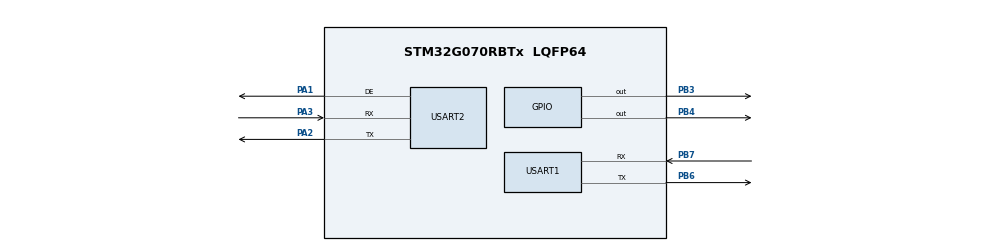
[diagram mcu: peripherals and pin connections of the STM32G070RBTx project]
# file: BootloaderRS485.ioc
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Dma.Request0=USART2_RX
Dma.USART2_RX.0.Direction=DMA_PERIPH_TO_MEMORY
Dma.USART2_RX.0.EventEnable=DISABLE
Dma.USART2_RX.0.Instance=DMA1_Channel1
Dma.USART2_RX.0.MemDataAlignment=DMA_MDATAALIGN_BYTE
Dma.USART2_RX.0.MemInc=DMA_MINC_ENABLE
Dma.USART2_RX.0.Mode=DMA_NORMAL
Dma.USART2_RX.0.PeriphDataAlignment=DMA_PDATAALIGN_BYTE
Dma.USART2_RX.0.PeriphInc=DMA_PINC_DISABLE
Dma.USART2_RX.0.Polarity=HAL_DMAMUX_REQ_GEN_RISING
Dma.USART2_RX.0.Priority=DMA_PRIORITY_LOW
Dma.USART2_RX.0.RequestNumber=1
Dma.USART2_RX.0.SignalID=NONE
Dma.USART2_RX.0.SyncEnable=DISABLE
Dma.USART2_RX.0.SyncPolarity=HAL_DMAMUX_SYNC_NO_EVENT
Dma.USART2_RX.0.SyncRequestNumber=1
Dma.USART2_RX.0.SyncSignalID=NONE
IWDG.Prescaler=IWDG_PRESCALER_4
Mcu.Family=STM32G0
Mcu.Name=STM32G070RBTx
Mcu.Package=LQFP64
NVIC.DMA1_Channel1_IRQn=true\:0\:0\:false\:false\:true\:false\:true\:true
NVIC.USART2_IRQn=true\:0\:0\:false\:false\:true\:true\:true\:true
PA1.Mode=Hardware Flow Control (RS485)
PA1.Signal=USART2_DE
PA2.Mode=Asynchronous
PA2.Signal=USART2_TX
PA3.Mode=Asynchronous
PA3.Signal=USART2_RX
PB3.Signal=GPIO_Output
PB4.Signal=GPIO_Output
PB6.Mode=Asynchronous
PB6.Signal=USART1_TX
PB7.Mode=Asynchronous
PB7.Signal=USART1_RX
PF0-OSC_IN\ (PF0).Mode=HSE-External-Oscillator
PF0-OSC_IN\ (PF0).Signal=RCC_OSC_IN
PF1-OSC_OUT\ (PF1).Mode=HSE-External-Oscillator
PF1-OSC_OUT\ (PF1).Signal=RCC_OSC_OUT
ProjectManager.HeapSize=0x200
ProjectManager.StackSize=0x400
ProjectManager.TargetToolchain=STM32CubeIDE
RCC.ADCFreq_Value=32000000
RCC.AHBFreq_Value=32000000
RCC.CortexFreq_Value=32000000
RCC.EXTERNAL_CLOCK_VALUE=48000
RCC.HCLKFreq_Value=32000000
RCC.HSE_VALUE=8000000
RCC.HSI_VALUE=16000000
RCC.LSE_VALUE=32768
RCC.PLLSourceVirtual=RCC_PLLSOURCE_HSE
RCC.SYSCLKFreq_VALUE=32000000
RCC.SYSCLKSource=RCC_SYSCLKSOURCE_PLLCLK
RCC.VCOOutputFreq_Value=64000000
USART1.VirtualMode-Asynchronous=VM_ASYNC
USART2.VirtualMode-Asynchronous=VM_ASYNC
USART2.VirtualMode-Hardware\ Flow\ Control\ (RS485)=VM_ASYNC
VP_IWDG_VS_IWDG.Mode=IWDG_Activate
board=custom

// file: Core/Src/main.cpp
/* USER CODE BEGIN Header */
/**
  ******************************************************************************
  * @file           : main.c
  * @brief          : Main program body
  ******************************************************************************
  * @attention
  *
  * Copyright (c) 2023 STMicroelectronics.
  * All rights reserved.
  *
  * This software is licensed under terms that can be found in the LICENSE file
  * in the root directory of this software component.
  * If no LICENSE file comes with this software, it is provided AS-IS.
  *
  ******************************************************************************
  */
/* USER CODE END Header */
#include "main.h"

/* USER CODE BEGIN Includes */
#include "RS485.hpp"
#include "FWUpdateApp.hpp"
#include "Logger.hpp"

#include "flash.hpp"

extern "C" {
	#include "RunApplication.h"
}
/* USER CODE END Includes */

IWDG_HandleTypeDef hiwdg;
UART_HandleTypeDef huart1;
UART_HandleTypeDef huart2;
DMA_HandleTypeDef hdma_usart2_rx;

/* USER CODE BEGIN PV */
FWUpdateApp fwUpdateApp;
SerialStream serialStream2(huart2, hdma_usart2_rx);
RS485 rs485(serialStream2, fwUpdateApp);
/* USER CODE END PV */

void SystemClock_Config(void);
static void MX_GPIO_Init(void);
static void MX_DMA_Init(void);
static void MX_USART1_UART_Init(void);
static void MX_USART2_UART_Init(void);
static void MX_IWDG_Init(void);

int main(void)
{

  /* MCU Configuration--------------------------------------------------------*/

  /* Reset of all peripherals, Initializes the Flash interface and the Systick. */
  HAL_Init();

  /* Configure the system clock */
  SystemClock_Config();

  /* USER CODE BEGIN SysInit */
  setLoggerUART(&huart1);
  /* USER CODE END SysInit */

  /* Initialize all configured peripherals */
  MX_GPIO_Init();
  MX_DMA_Init();
  MX_USART1_UART_Init();
  MX_USART2_UART_Init();
  MX_IWDG_Init();
  /* USER CODE BEGIN 2 */

  serialStream2.init();
  log(LogLevel::Status, "Bootloader v5");
  logPrint(".");

  /* USER CODE END 2 */

  /* Infinite loop */
  /* USER CODE BEGIN WHILE */
  int delay = 10;
  int countdown = 3000 / delay;
  int flashEvery = 100 / delay;
  while(countdown-- >= 0)
  {
	  if(countdown % flashEvery == 0) {
		  HAL_GPIO_TogglePin(GPIOB
				  , GPIO_PIN_4);
	  }

	  rs485.update();

	  fwUpdateApp.update();
	  if(fwUpdateApp.isFWIncoming()) {
		  countdown = 10000 / delay;
		  logPrint("_");
	  }
	  else {
		  logPrint(".");
	  }

	  HAL_IWDG_Refresh(&hiwdg);
	  HAL_Delay(delay);
    /* USER CODE END WHILE */

    /* USER CODE BEGIN 3 */
  }
  log(LogLevel::Status, "Jumping to Application...");
  run_application();
  /* USER CODE END 3 */
}

void SystemClock_Config(void)
{
  RCC_OscInitTypeDef RCC_OscInitStruct = {0};
  RCC_ClkInitTypeDef RCC_ClkInitStruct = {0};

  /** Configure the main internal regulator output voltage
  */
  HAL_PWREx_ControlVoltageScaling(PWR_REGULATOR_VOLTAGE_SCALE1);

  /** Initializes the RCC Oscillators according to the specified parameters
  * in the RCC_OscInitTypeDef structure.
  */
  RCC_OscInitStruct.OscillatorType = RCC_OSCILLATORTYPE_HSE;
  RCC_OscInitStruct.HSEState = RCC_HSE_ON;
  RCC_OscInitStruct.PLL.PLLState = RCC_PLL_ON;
  RCC_OscInitStruct.PLL.PLLSource = RCC_PLLSOURCE_HSE;
  RCC_OscInitStruct.PLL.PLLM = RCC_PLLM_DIV1;
  RCC_OscInitStruct.PLL.PLLN = 16;
  RCC_OscInitStruct.PLL.PLLP = RCC_PLLP_DIV2;
  RCC_OscInitStruct.PLL.PLLR = RCC_PLLR_DIV2;
  if (HAL_RCC_OscConfig(&RCC_OscInitStruct) != HAL_OK)
  {
    Error_Handler();
  }

  /** Initializes the CPU, AHB and APB buses clocks
  */
  RCC_ClkInitStruct.ClockType = RCC_CLOCKTYPE_HCLK|RCC_CLOCKTYPE_SYSCLK
                              |RCC_CLOCKTYPE_PCLK1;
  RCC_ClkInitStruct.SYSCLKSource = RCC_SYSCLKSOURCE_PLLCLK;
  RCC_ClkInitStruct.AHBCLKDivider = RCC_SYSCLK_DIV1;
  RCC_ClkInitStruct.APB1CLKDivider = RCC_HCLK_DIV1;

  if (HAL_RCC_ClockConfig(&RCC_ClkInitStruct, FLASH_LATENCY_2) != HAL_OK)
  {
    Error_Handler();
  }
}

static void MX_IWDG_Init(void)
{

  hiwdg.Instance = IWDG;
  hiwdg.Init.Prescaler = IWDG_PRESCALER_32;
  hiwdg.Init.Window = 4095;
  hiwdg.Init.Reload = 4095;
  if (HAL_IWDG_Init(&hiwdg) != HAL_OK)
  {
    Error_Handler();
  }

}

static void MX_USART1_UART_Init(void)
{

  huart1.Instance = USART1;
  huart1.Init.BaudRate = 115200;
  huart1.Init.WordLength = UART_WORDLENGTH_8B;
  huart1.Init.StopBits = UART_STOPBITS_1;
  huart1.Init.Parity = UART_PARITY_NONE;
  huart1.Init.Mode = UART_MODE_TX_RX;
  huart1.Init.HwFlowCtl = UART_HWCONTROL_NONE;
  huart1.Init.OverSampling = UART_OVERSAMPLING_16;
  huart1.Init.OneBitSampling = UART_ONE_BIT_SAMPLE_DISABLE;
  huart1.Init.ClockPrescaler = UART_PRESCALER_DIV1;
  huart1.AdvancedInit.AdvFeatureInit = UART_ADVFEATURE_NO_INIT;
  if (HAL_UART_Init(&huart1) != HAL_OK)
  {
    Error_Handler();
  }
  if (HAL_UARTEx_SetTxFifoThreshold(&huart1, UART_TXFIFO_THRESHOLD_1_8) != HAL_OK)
  {
    Error_Handler();
  }
  if (HAL_UARTEx_SetRxFifoThreshold(&huart1, UART_RXFIFO_THRESHOLD_1_8) != HAL_OK)
  {
    Error_Handler();
  }
  if (HAL_UARTEx_DisableFifoMode(&huart1) != HAL_OK)
  {
    Error_Handler();
  }

}

static void MX_USART2_UART_Init(void)
{

  huart2.Instance = USART2;
  huart2.Init.BaudRate = 115200;
  huart2.Init.WordLength = UART_WORDLENGTH_8B;
  huart2.Init.StopBits = UART_STOPBITS_1;
  huart2.Init.Parity = UART_PARITY_NONE;
  huart2.Init.Mode = UART_MODE_TX_RX;
  huart2.Init.HwFlowCtl = UART_HWCONTROL_NONE;
  huart2.Init.OverSampling = UART_OVERSAMPLING_16;
  huart2.Init.OneBitSampling = UART_ONE_BIT_SAMPLE_DISABLE;
  huart2.Init.ClockPrescaler = UART_PRESCALER_DIV1;
  huart2.AdvancedInit.AdvFeatureInit = UART_ADVFEATURE_NO_INIT;
  if (HAL_RS485Ex_Init(&huart2, UART_DE_POLARITY_HIGH, 0, 0) != HAL_OK)
  {
    Error_Handler();
  }
  if (HAL_UARTEx_SetTxFifoThreshold(&huart2, UART_TXFIFO_THRESHOLD_1_8) != HAL_OK)
  {
    Error_Handler();
  }
  if (HAL_UARTEx_SetRxFifoThreshold(&huart2, UART_RXFIFO_THRESHOLD_1_8) != HAL_OK)
  {
    Error_Handler();
  }
  if (HAL_UARTEx_DisableFifoMode(&huart2) != HAL_OK)
  {
    Error_Handler();
  }

}

static void MX_DMA_Init(void)
{

  /* DMA controller clock enable */
  __HAL_RCC_DMA1_CLK_ENABLE();

  /* DMA interrupt init */
  /* DMA1_Channel1_IRQn interrupt configuration */
  HAL_NVIC_SetPriority(DMA1_Channel1_IRQn, 0, 0);
  HAL_NVIC_EnableIRQ(DMA1_Channel1_IRQn);

}

static void MX_GPIO_Init(void)
{
  GPIO_InitTypeDef GPIO_InitStruct = {0};

  /* GPIO Ports Clock Enable */
  __HAL_RCC_GPIOF_CLK_ENABLE();
  __HAL_RCC_GPIOA_CLK_ENABLE();
  __HAL_RCC_GPIOB_CLK_ENABLE();

  /*Configure GPIO pin Output Level */
  HAL_GPIO_WritePin(GPIOB, GPIO_PIN_3|GPIO_PIN_4, GPIO_PIN_RESET);

  /*Configure GPIO pins : PB3 PB4 */
  GPIO_InitStruct.Pin = GPIO_PIN_3|GPIO_PIN_4;
  GPIO_InitStruct.Mode = GPIO_MODE_OUTPUT_PP;
  GPIO_InitStruct.Pull = GPIO_NOPULL;
  GPIO_InitStruct.Speed = GPIO_SPEED_FREQ_LOW;
  HAL_GPIO_Init(GPIOB, &GPIO_InitStruct);

}

void Error_Handler(void)
{
  __disable_irq();
  while (1)
  {
  }
}
